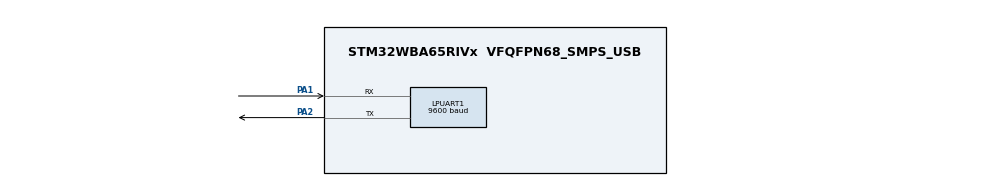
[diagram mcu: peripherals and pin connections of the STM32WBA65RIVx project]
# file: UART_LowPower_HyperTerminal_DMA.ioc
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CORTEX_M33_NS.userName=CORTEX_M33
GPDMA1.DESTINC_GPDMACH2=DMA_DINC_INCREMENTED
GPDMA1.DIRECTION_GPDMACH1=DMA_MEMORY_TO_PERIPH
GPDMA1.IPHANDLE_GPDMACH1-SIMPLEREQUEST_GPDMACH1=__NULL
GPDMA1.IPHANDLE_GPDMACH2-SIMPLEREQUEST_GPDMACH2=__NULL
GPDMA1.PRIORITY_GPDMACH1=DMA_LOW_PRIORITY_HIGH_WEIGHT
GPDMA1.RECAP_GPDMACH1=GPDMA1_REQUEST_LPUART1_TX
GPDMA1.RECAP_GPDMACH2=GPDMA1_REQUEST_LPUART1_RX
GPDMA1.REQUEST_GPDMACH1=GPDMA1_REQUEST_LPUART1_TX
GPDMA1.REQUEST_GPDMACH2=GPDMA1_REQUEST_LPUART1_RX
GPDMA1.SRCINC_GPDMACH1=DMA_SINC_INCREMENTED
LPUART1.BaudRate=9600
LPUART1.ClockPrescaler=UART_PRESCALER_DIV1
LPUART1.DMADisableonRxErrorParam=UART_ADVFEATURE_DMA_ENABLEONRXERROR
LPUART1.DataInvertParam=UART_ADVFEATURE_DATAINV_DISABLE
LPUART1.MSBFirstParam=UART_ADVFEATURE_MSBFIRST_DISABLE
LPUART1.Mode=UART_MODE_TX_RX
LPUART1.OneBitSampling=UART_ONE_BIT_SAMPLE_DISABLE
LPUART1.OverrunDisableParam=UART_ADVFEATURE_OVERRUN_ENABLE
LPUART1.Parity=UART_PARITY_ODD
LPUART1.RxPinLevelInvertParam=UART_ADVFEATURE_RXINV_DISABLE
LPUART1.StopBits=UART_STOPBITS_1
LPUART1.SwapParam=UART_ADVFEATURE_SWAP_DISABLE
LPUART1.TxPinLevelInvertParam=UART_ADVFEATURE_TXINV_DISABLE
LPUART1.WordLength=UART_WORDLENGTH_8B
Mcu.Family=STM32WBA
Mcu.Name=STM32WBA65RIVx
Mcu.Package=VFQFPN68_SMPS_USB
NVIC.GPDMA1_Channel1_IRQn=true\:0\:0\:false\:false\:true\:false\:true\:true
NVIC.GPDMA1_Channel2_IRQn=true\:0\:0\:false\:false\:true\:false\:true\:true
NVIC.LPUART1_IRQn=true\:0\:0\:false\:false\:true\:true\:true\:true
NVIC.PriorityGroup=NVIC_PRIORITYGROUP_4
OSC_IN.Mode=HSE-External-Oscillator
OSC_IN.PinAttribute=CortexM33
OSC_IN.Signal=RCC_OSC_IN
OSC_OUT.Mode=HSE-External-Oscillator
OSC_OUT.PinAttribute=CortexM33
OSC_OUT.Signal=RCC_OSC_OUT
PA1.GPIO_PuPd=GPIO_PULLUP
PA1.Mode=Asynchronous
PA1.PinAttribute=CortexM33
PA1.Signal=LPUART1_RX
PA2.GPIO_PuPd=GPIO_PULLUP
PA2.Mode=Asynchronous
PA2.PinAttribute=CortexM33
PA2.Signal=LPUART1_TX
ProjectManager.HeapSize=0x200
ProjectManager.StackSize=0x400
ProjectManager.TargetToolchain=EWARM V9.20
RCC.ADCFreq_Value=100000000
RCC.AHB5CLKDivider=DIV4
RCC.AHBFreq_Value=100000000
RCC.APB1Freq_Value=100000000
RCC.APB1TimFreq_Value=100000000
RCC.APB2Freq_Value=100000000
RCC.APB2TimFreq_Value=100000000
RCC.CortexFreq_Value=12500000
RCC.HCLKFreq_Value=100000000
RCC.HSE_VALUE=32000000
RCC.HSI_VALUE=16000000
RCC.LPUART1CLockSelectionVirtual=RCC_LPUART1CLKSOURCE_HSI
RCC.LSE_VALUE=32768
RCC.LSI1_VALUE=32000
RCC.LSI2_VALUE=32000
RCC.PLLFRACN=4096
RCC.PLLM=2
RCC.PLLN=12
RCC.PLLSourceVirtual=RCC_PLLSOURCE_HSE
RCC.SYSCLKFreq_VALUE=100000000
RCC.SYSCLKSourceVirtual=RCC_SYSCLKSOURCE_PLLCLK
RCC.VCOOutputFreq_Value=200000000
VP_CORTEX_M33_NS_VS_Hclk.Mode=Hclk_Mode
VP_GPDMA1_VS_GPDMACH1.Mode=SIMPLEREQUEST_GPDMACH1
VP_GPDMA1_VS_GPDMACH2.Mode=SIMPLEREQUEST_GPDMACH2
VP_ICACHE_VS_ICACHE.Mode=DirectMappedCache
VP_MEMORYMAP_VS_MEMORYMAP.Mode=CurAppReg
VP_PWR_VS_SECSignals.Mode=Security/Privilege
board=custom

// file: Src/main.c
/* USER CODE BEGIN Header */
/**
  ******************************************************************************
  * @file           : main.c
  * @brief          : Main program body
  ******************************************************************************
  * @attention
  *
  * Copyright (c) 2025 STMicroelectronics.
  * All rights reserved.
  *
  * This software is licensed under terms that can be found in the LICENSE file
  * in the root directory of this software component.
  * If no LICENSE file comes with this software, it is provided AS-IS.
  *
  ******************************************************************************
  */
/* USER CODE END Header */
#include "main.h"

/* USER CODE BEGIN Includes */
#include "stm32wbaxx_nucleo.h"
/* USER CODE END Includes */

UART_HandleTypeDef hlpuart1;
DMA_HandleTypeDef handle_GPDMA1_Channel2;
DMA_HandleTypeDef handle_GPDMA1_Channel1;

/* USER CODE BEGIN PV */
/* Private variables ---------------------------------------------------------*/
/* Buffer used for transmission */
uint8_t aTxBuffer[] = "\n\r ****UART-Hyperterminal communication based on DMA****\n\r Enter 10 characters using keyboard :\n\r";

/* Buffer used for reception */
uint8_t aRxBuffer[RXBUFFERSIZE];
/* USER CODE END PV */

void SystemClock_Config(void);
static void MX_GPIO_Init(void);
static void MX_GPDMA1_Init(void);
static void MX_LPUART1_UART_Init(void);
static void MX_ICACHE_Init(void);

int main(void)
{

  /* USER CODE BEGIN 1 */
  /* STM32WBAxx HAL library initialization:
       - Systick timer is configured by default as source of time base, but user
             can eventually implement his proper time base source (a general purpose
             timer for example or other time source), keeping in mind that Time base
             duration should be kept 1ms since PPP_TIMEOUT_VALUEs are defined and
             handled in milliseconds basis.
       - Set NVIC Group Priority to 4
       - Low Level Initialization
     */
  /* USER CODE END 1 */

  /* MCU Configuration--------------------------------------------------------*/

  /* Reset of all peripherals, Initializes the Flash interface and the Systick. */
  HAL_Init();

  /* Configure the system clock */
  SystemClock_Config();

  /* Initialize all configured peripherals */
  MX_GPIO_Init();
  MX_GPDMA1_Init();
  MX_LPUART1_UART_Init();
  MX_ICACHE_Init();
  /* USER CODE BEGIN 2 */
  /* Configure LD1, LD2 and LD3 */
  BSP_LED_Init(LD1);
  BSP_LED_Init(LD2);
  BSP_LED_Init(LD3);

  /*##-1- Start the transmission process #####################################*/
  /* User start transmission data through "TxBuffer" buffer */
  if (HAL_UART_Transmit_DMA(&hlpuart1, (uint8_t *)aTxBuffer, TXBUFFERSIZE) != HAL_OK)
  {
    /* Transfer error in transmission process */
    Error_Handler();
  }

  /*##-2- Put UART peripheral in reception process ###########################*/
  /* Any data received will be stored in "RxBuffer" buffer : the number max of
     data received is 10 */
  if (HAL_UART_Receive_DMA(&hlpuart1, (uint8_t *)aRxBuffer, RXBUFFERSIZE) != HAL_OK)
  {
    /* Transfer error in reception process */
    Error_Handler();
  }

  /*##-3- Wait for the end of the transfer ###################################*/
  /*  Before starting a new communication transfer, you need to check the current
      state of the peripheral; if it is busy you need to wait for the end of current
      transfer before starting a new one.
      For simplicity reasons, this example is just waiting till the end of the
      transfer, but application may perform other tasks while transfer operation
      is ongoing. */
  while (HAL_UART_GetState(&hlpuart1) != HAL_UART_STATE_READY)
  {
  }

  /*##-4- Send the received Buffer ###########################################*/
  if (HAL_UART_Transmit_DMA(&hlpuart1, (uint8_t *)aRxBuffer, RXBUFFERSIZE) != HAL_OK)
  {
    /* Transfer error in transmission process */
    Error_Handler();
  }

  /*##-5- Wait for the end of the transfer ###################################*/
  /*  Before starting a new communication transfer, you need to check the current
      state of the peripheral; if it is busy you need to wait for the end of current
      transfer before starting a new one.
      For simplicity reasons, this example is just waiting till the end of the
      transfer, but application may perform other tasks while transfer operation
      is ongoing. */
  while (HAL_UART_GetState(&hlpuart1) != HAL_UART_STATE_READY)
  {
  }

  /* USER CODE END 2 */

  /* Infinite loop */
  while (1)
  {

  }
}

void SystemClock_Config(void)
{
  RCC_OscInitTypeDef RCC_OscInitStruct = {0};
  RCC_ClkInitTypeDef RCC_ClkInitStruct = {0};

  /** Supply configuration update enable
  */
  HAL_PWREx_ConfigSupply(PWR_LDO_SUPPLY);

  /** Configure the main internal regulator output voltage
  */
  if (HAL_PWREx_ControlVoltageScaling(PWR_REGULATOR_VOLTAGE_SCALE1) != HAL_OK)
  {
    Error_Handler();
  }

  /** Initializes the CPU, AHB and APB busses clocks
  */
  RCC_OscInitStruct.OscillatorType = RCC_OSCILLATORTYPE_HSI|RCC_OSCILLATORTYPE_HSE;
  RCC_OscInitStruct.HSEState = RCC_HSE_ON;
  RCC_OscInitStruct.HSEDiv = RCC_HSE_DIV1;
  RCC_OscInitStruct.HSIState = RCC_HSI_ON;
  RCC_OscInitStruct.HSICalibrationValue = RCC_HSICALIBRATION_DEFAULT;
  RCC_OscInitStruct.PLL1.PLLState = RCC_PLL_ON;
  RCC_OscInitStruct.PLL1.PLLSource = RCC_PLLSOURCE_HSE;
  RCC_OscInitStruct.PLL1.PLLM = 2;
  RCC_OscInitStruct.PLL1.PLLN = 12;
  RCC_OscInitStruct.PLL1.PLLP = 2;
  RCC_OscInitStruct.PLL1.PLLQ = 2;
  RCC_OscInitStruct.PLL1.PLLR = 2;
  RCC_OscInitStruct.PLL1.PLLFractional = 4096;
  if (HAL_RCC_OscConfig(&RCC_OscInitStruct) != HAL_OK)
  {
    Error_Handler();
  }

  /** Initializes the CPU, AHB and APB busses clocks
  */
  RCC_ClkInitStruct.ClockType = RCC_CLOCKTYPE_HCLK|RCC_CLOCKTYPE_SYSCLK
                              |RCC_CLOCKTYPE_PCLK1|RCC_CLOCKTYPE_PCLK2
                              |RCC_CLOCKTYPE_PCLK7|RCC_CLOCKTYPE_HCLK5;
  RCC_ClkInitStruct.SYSCLKSource = RCC_SYSCLKSOURCE_PLLCLK;
  RCC_ClkInitStruct.AHBCLKDivider = RCC_SYSCLK_DIV1;
  RCC_ClkInitStruct.APB1CLKDivider = RCC_HCLK_DIV1;
  RCC_ClkInitStruct.APB2CLKDivider = RCC_HCLK_DIV1;
  RCC_ClkInitStruct.APB7CLKDivider = RCC_HCLK_DIV1;
  RCC_ClkInitStruct.AHB5_PLL1_CLKDivider = RCC_SYSCLK_PLL1_DIV4;
  RCC_ClkInitStruct.AHB5_HSEHSI_CLKDivider = RCC_SYSCLK_HSEHSI_DIV1;

  if (HAL_RCC_ClockConfig(&RCC_ClkInitStruct, FLASH_LATENCY_3) != HAL_OK)
  {
    Error_Handler();
  }
}

static void MX_GPDMA1_Init(void)
{

  /* Peripheral clock enable */
  __HAL_RCC_GPDMA1_CLK_ENABLE();

  /* GPDMA1 interrupt Init */
    HAL_NVIC_SetPriority(GPDMA1_Channel1_IRQn, 0, 0);
    HAL_NVIC_EnableIRQ(GPDMA1_Channel1_IRQn);
    HAL_NVIC_SetPriority(GPDMA1_Channel2_IRQn, 0, 0);
    HAL_NVIC_EnableIRQ(GPDMA1_Channel2_IRQn);

}

static void MX_ICACHE_Init(void)
{

  /** Enable instruction cache in 1-way (direct mapped cache)
  */
  if (HAL_ICACHE_ConfigAssociativityMode(ICACHE_1WAY) != HAL_OK)
  {
    Error_Handler();
  }
  if (HAL_ICACHE_Enable() != HAL_OK)
  {
    Error_Handler();
  }

}

static void MX_LPUART1_UART_Init(void)
{

  hlpuart1.Instance = LPUART1;
  hlpuart1.Init.BaudRate = 9600;
  hlpuart1.Init.WordLength = UART_WORDLENGTH_8B;
  hlpuart1.Init.StopBits = UART_STOPBITS_1;
  hlpuart1.Init.Parity = UART_PARITY_ODD;
  hlpuart1.Init.Mode = UART_MODE_TX_RX;
  hlpuart1.Init.HwFlowCtl = UART_HWCONTROL_NONE;
  hlpuart1.Init.OneBitSampling = UART_ONE_BIT_SAMPLE_DISABLE;
  hlpuart1.Init.ClockPrescaler = UART_PRESCALER_DIV1;
  hlpuart1.AdvancedInit.AdvFeatureInit = UART_ADVFEATURE_NO_INIT;
  hlpuart1.FifoMode = UART_FIFOMODE_DISABLE;
  if (HAL_UART_Init(&hlpuart1) != HAL_OK)
  {
    Error_Handler();
  }
  if (HAL_UARTEx_SetTxFifoThreshold(&hlpuart1, UART_TXFIFO_THRESHOLD_1_8) != HAL_OK)
  {
    Error_Handler();
  }
  if (HAL_UARTEx_SetRxFifoThreshold(&hlpuart1, UART_RXFIFO_THRESHOLD_1_8) != HAL_OK)
  {
    Error_Handler();
  }
  if (HAL_UARTEx_DisableFifoMode(&hlpuart1) != HAL_OK)
  {
    Error_Handler();
  }

}

static void MX_GPIO_Init(void)
{

  /* GPIO Ports Clock Enable */
  __HAL_RCC_GPIOA_CLK_ENABLE();

}

/* USER CODE BEGIN 4 */
/**
  * @brief  Tx Transfer completed callback
  * @param  huart: UART handle.
  * @note   This example shows a simple way to report end of DMA Tx transfer, and
  *         you can add your own implementation.
  * @retval None
  */
void HAL_UART_TxCpltCallback(UART_HandleTypeDef *huart)
{
  /* Turn LED1 on: Transfer in transmission process is correct */
  BSP_LED_On(LD1);
}

/**
  * @brief  Rx Transfer completed callback
  * @param  huart: UART handle
  * @note   This example shows a simple way to report end of DMA Rx transfer, and
  *         you can add your own implementation.
  * @retval None
  */
void HAL_UART_RxCpltCallback(UART_HandleTypeDef *huart)
{
  /* Turn LD2 on: Transfer in reception process is correct */
  BSP_LED_On(LD2);
}

/**
  * @brief  UART error callbacks
  * @param  huart: UART handle
  * @note   This example shows a simple way to report transfer error, and you can
  *         add your own implementation.
  * @retval None
  */
void HAL_UART_ErrorCallback(UART_HandleTypeDef *huart)
{
  /* Turn LD3 on: Transfer error in reception/transmission process */
  BSP_LED_On(LD3);
}
/* USER CODE END 4 */

void Error_Handler(void)
{
  __disable_irq();
  while (1)
  {
  }
}
